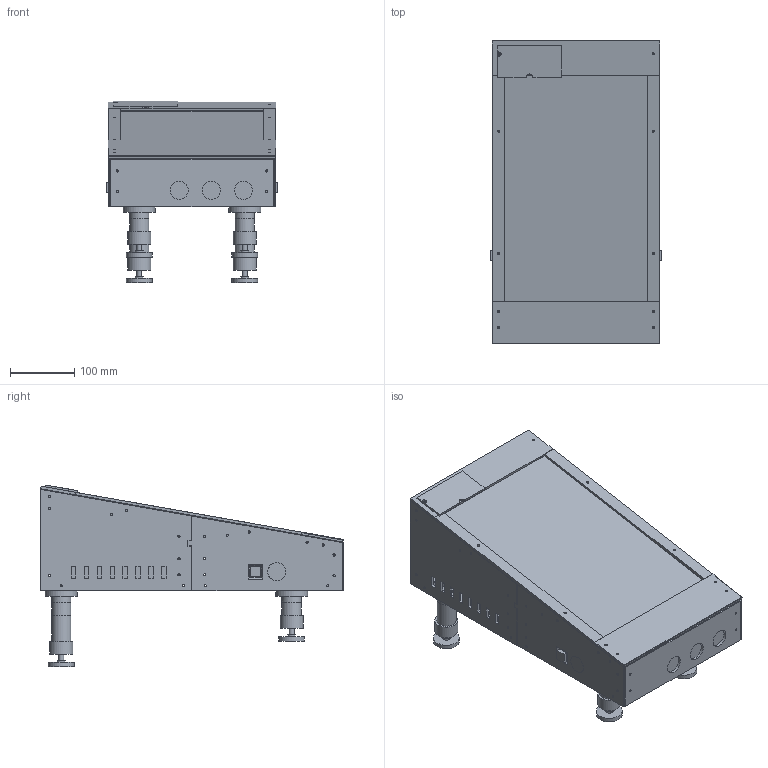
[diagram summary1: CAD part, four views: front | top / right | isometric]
STEP (ISO 10303-21) file: header records copied from the file, then geometry measured from it (millimetres).
FILE_DESCRIPTION(('Open CASCADE Model'),'2;1');
FILE_NAME('Open CASCADE Shape Model','2026-11-09T00:20:32',('Author'),( 'Open CASCADE'),'Open CASCADE STEP processor 7.8','Open CASCADE 7.8' ,'Unknown');
FILE_SCHEMA(('AUTOMOTIVE_DESIGN { 1 0 10303 214 1 1 1 1 }'));
Length unit declared in the file: millimetre
Products named in the file (89): Mini_VPin_Prototype_V1_12; left_front_wall; left_rear_wall; right_front_wall; right_rear_wall; front_button_panel; rear_vent_panel; corner_left_front_24; corner_left_front_56; corner_left_rear_24; corner_left_rear_128; corner_right_front_24; corner_right_front_56; corner_right_rear_24; corner_right_rear_128; splice_left; splice_right; floor_block_left_28; floor_block_left_218; floor_block_left_252; floor_block_left_442; floor_block_right_28; floor_block_right_218; floor_block_right_252; floor_block_right_442; bottom_front; bottom_rear; foot_backing_left_front; foot_receiver_left_front; foot_extension_left_front_1_20mm; foot_terminal_left_front; REFERENCE_swivel_rubber_pad_left_front; foot_backing_left_rear; foot_receiver_left_rear; foot_extension_left_rear_1_20mm; foot_extension_left_rear_2_40mm; foot_terminal_left_rear; REFERENCE_swivel_rubber_pad_left_rear; foot_backing_right_front; foot_receiver_right_front ...
Assembly tree (88 placements, depth 2):
  Mini_VPin_Prototype_V1_12
    left_front_wall
    left_rear_wall
    right_front_wall
    right_rear_wall
    front_button_panel
    rear_vent_panel
    corner_left_front_24
    corner_left_front_56
    corner_left_rear_24
    corner_left_rear_128
    corner_right_front_24
    corner_right_front_56
    corner_right_rear_24
    corner_right_rear_128
    splice_left
    splice_right
    floor_block_left_28
    floor_block_left_218
    floor_block_left_252
    floor_block_left_442
    floor_block_right_28
    floor_block_right_218
    floor_block_right_252
    floor_block_right_442
    bottom_front
    bottom_rear
    foot_backing_left_front
    foot_receiver_left_front
    foot_extension_left_front_1_20mm
    foot_terminal_left_front
    REFERENCE_swivel_rubber_pad_left_front
    foot_backing_left_rear
    foot_receiver_left_rear
    foot_extension_left_rear_1_20mm
    foot_extension_left_rear_2_40mm
    foot_terminal_left_rear
    REFERENCE_swivel_rubber_pad_left_rear
    foot_backing_right_front
    foot_receiver_right_front
    foot_extension_right_front_1_20mm
    foot_terminal_right_front
    REFERENCE_swivel_rubber_pad_right_front
    foot_backing_right_rear
    foot_receiver_right_rear
    foot_extension_right_rear_1_20mm
    foot_extension_right_rear_2_40mm
    foot_terminal_right_rear
    REFERENCE_swivel_rubber_pad_right_rear
    top_block_left_25
    top_block_left_50
    top_block_left_140
    top_block_left_330
    top_block_left_450
    top_block_right_25
    top_block_right_50
    top_block_right_140
    top_block_right_330
    top_block_right_450
    monitor_saddle_left_180
Bounding box: 267 x 470.54 x 282.59 mm (x, y, z)
Volume: 7623923.4 mm3; surface area: 1507758.3 mm2
Topology: 88 solids, 88 shells, 1635 faces, 4087 edges, 2722 vertices
Faces by surface type: plane 1296, cylinder 313, extrusion 20, bspline 4, cone 2
Full cylindrical faces by diameter (mm): 3.4 x158, 4.5 x52, 6 x2, 6.4 x2, 8 x4, 8.4 x16, 8.7 x14, 12 x4, 27.8 x2, 28 x5, 30 x10, 36 x4, 40 x6, 50 x8
Entity records: 114635 total; most frequent: CARTESIAN_POINT 29486, DIRECTION 14993, VECTOR 9529, LINE 9509, ORIENTED_EDGE 8174, PCURVE 8174, DEFINITIONAL_REPRESENTATION 8174, EDGE_CURVE 4087
One B-rep face of a CAD part: STEP entity #116369.
In plain terms, the planar face has unit normal (0, -0.174, 0.985).
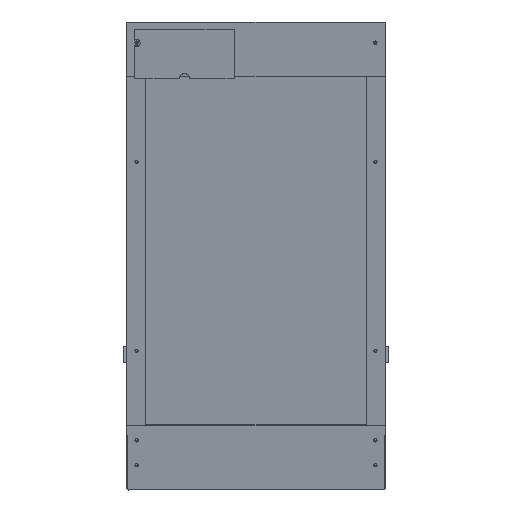
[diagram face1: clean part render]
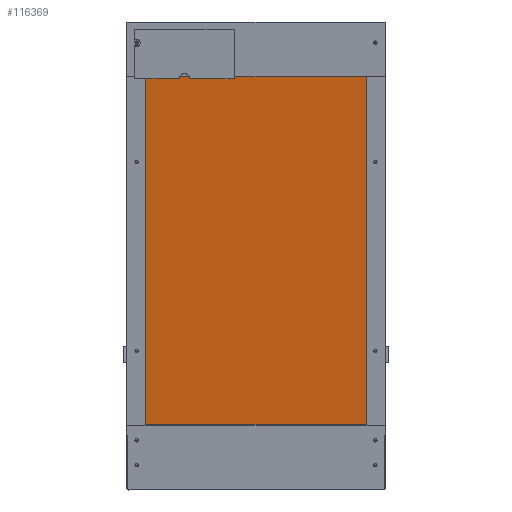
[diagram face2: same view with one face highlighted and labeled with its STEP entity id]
Its self-contained STEP definition (entity closure, numbers rounded to 3 decimals):
#116200 = PLANE('',#116201);
#116201 = AXIS2_PLACEMENT_3D('',#116202,#116203,#116204);
#116202 = CARTESIAN_POINT('',(18.1,64.,86.285));
#116203 = DIRECTION('',(-0.,1.,0.));
#116204 = DIRECTION('',(0.,0.,-1.));
#116228 = PLANE('',#116229);
#116229 = AXIS2_PLACEMENT_3D('',#116230,#116231,#116232);
#116230 = CARTESIAN_POINT('',(241.9,240.675,111.437));
#116231 = DIRECTION('',(1.,0.,0.));
#116232 = DIRECTION('',(-0.,0.,1.));
#116256 = PLANE('',#116257);
#116257 = AXIS2_PLACEMENT_3D('',#116258,#116259,#116260);
#116258 = CARTESIAN_POINT('',(18.1,417.349,136.59));
#116259 = DIRECTION('',(0.,-1.,0.));
#116260 = DIRECTION('',(0.,0.,1.));
#116282 = PLANE('',#116283);
#116283 = AXIS2_PLACEMENT_3D('',#116284,#116285,#116286);
#116284 = CARTESIAN_POINT('',(18.1,240.675,111.437));
#116285 = DIRECTION('',(1.,0.,0.));
#116286 = DIRECTION('',(-0.,0.,1.));
#116299 = VERTEX_POINT('',#116300);
#116300 = CARTESIAN_POINT('',(241.9,417.349,148.59));
#116321 = EDGE_CURVE('',#116322,#116299,#116324,.T.);
#116322 = VERTEX_POINT('',#116323);
#116323 = CARTESIAN_POINT('',(18.1,417.349,148.59));
#116324 = SURFACE_CURVE('',#116325,(#116329,#116336),.PCURVE_S1.);
#116325 = LINE('',#116326,#116327);
#116326 = CARTESIAN_POINT('',(18.1,417.349,148.59));
#116327 = VECTOR('',#116328,1.);
#116328 = DIRECTION('',(1.,0.,0.));
#116329 = PCURVE('',#116256,#116330);
#116330 = DEFINITIONAL_REPRESENTATION('',(#116331),#116335);
#116331 = LINE('',#116332,#116333);
#116332 = CARTESIAN_POINT('',(12.,0.));
#116333 = VECTOR('',#116334,1.);
#116334 = DIRECTION('',(0.,-1.));
#116335 = ( GEOMETRIC_REPRESENTATION_CONTEXT(2) 
PARAMETRIC_REPRESENTATION_CONTEXT() REPRESENTATION_CONTEXT('2D SPACE',''
  ) );
#116336 = PCURVE('',#116337,#116342);
#116337 = PLANE('',#116338);
#116338 = AXIS2_PLACEMENT_3D('',#116339,#116340,#116341);
#116339 = CARTESIAN_POINT('',(18.1,417.349,148.59));
#116340 = DIRECTION('',(0.,0.174,-0.985));
#116341 = DIRECTION('',(0.,-0.985,-0.174));
#116342 = DEFINITIONAL_REPRESENTATION('',(#116343),#116347);
#116343 = LINE('',#116344,#116345);
#116344 = CARTESIAN_POINT('',(0.,0.));
#116345 = VECTOR('',#116346,1.);
#116346 = DIRECTION('',(0.,-1.));
#116347 = ( GEOMETRIC_REPRESENTATION_CONTEXT(2) 
PARAMETRIC_REPRESENTATION_CONTEXT() REPRESENTATION_CONTEXT('2D SPACE',''
  ) );
#116369 = ADVANCED_FACE('',(#116370),#116337,.F.);
#116370 = FACE_BOUND('',#116371,.F.);
#116371 = EDGE_LOOP('',(#116372,#116373,#116396,#116419));
#116372 = ORIENTED_EDGE('',*,*,#116321,.T.);
#116373 = ORIENTED_EDGE('',*,*,#116374,.T.);
#116374 = EDGE_CURVE('',#116299,#116375,#116377,.T.);
#116375 = VERTEX_POINT('',#116376);
#116376 = CARTESIAN_POINT('',(241.9,64.,86.285));
#116377 = SURFACE_CURVE('',#116378,(#116382,#116389),.PCURVE_S1.);
#116378 = LINE('',#116379,#116380);
#116379 = CARTESIAN_POINT('',(241.9,417.349,148.59));
#116380 = VECTOR('',#116381,1.);
#116381 = DIRECTION('',(0.,-0.985,-0.174));
#116382 = PCURVE('',#116337,#116383);
#116383 = DEFINITIONAL_REPRESENTATION('',(#116384),#116388);
#116384 = LINE('',#116385,#116386);
#116385 = CARTESIAN_POINT('',(0.,-223.8));
#116386 = VECTOR('',#116387,1.);
#116387 = DIRECTION('',(1.,0.));
#116388 = ( GEOMETRIC_REPRESENTATION_CONTEXT(2) 
PARAMETRIC_REPRESENTATION_CONTEXT() REPRESENTATION_CONTEXT('2D SPACE',''
  ) );
#116389 = PCURVE('',#116228,#116390);
#116390 = DEFINITIONAL_REPRESENTATION('',(#116391),#116395);
#116391 = LINE('',#116392,#116393);
#116392 = CARTESIAN_POINT('',(37.152,-176.675));
#116393 = VECTOR('',#116394,1.);
#116394 = DIRECTION('',(-0.174,0.985));
#116395 = ( GEOMETRIC_REPRESENTATION_CONTEXT(2) 
PARAMETRIC_REPRESENTATION_CONTEXT() REPRESENTATION_CONTEXT('2D SPACE',''
  ) );
#116396 = ORIENTED_EDGE('',*,*,#116397,.F.);
#116397 = EDGE_CURVE('',#116398,#116375,#116400,.T.);
#116398 = VERTEX_POINT('',#116399);
#116399 = CARTESIAN_POINT('',(18.1,64.,86.285));
#116400 = SURFACE_CURVE('',#116401,(#116405,#116412),.PCURVE_S1.);
#116401 = LINE('',#116402,#116403);
#116402 = CARTESIAN_POINT('',(18.1,64.,86.285));
#116403 = VECTOR('',#116404,1.);
#116404 = DIRECTION('',(1.,0.,0.));
#116405 = PCURVE('',#116337,#116406);
#116406 = DEFINITIONAL_REPRESENTATION('',(#116407),#116411);
#116407 = LINE('',#116408,#116409);
#116408 = CARTESIAN_POINT('',(358.8,0.));
#116409 = VECTOR('',#116410,1.);
#116410 = DIRECTION('',(0.,-1.));
#116411 = ( GEOMETRIC_REPRESENTATION_CONTEXT(2) 
PARAMETRIC_REPRESENTATION_CONTEXT() REPRESENTATION_CONTEXT('2D SPACE',''
  ) );
#116412 = PCURVE('',#116200,#116413);
#116413 = DEFINITIONAL_REPRESENTATION('',(#116414),#116418);
#116414 = LINE('',#116415,#116416);
#116415 = CARTESIAN_POINT('',(0.,0.));
#116416 = VECTOR('',#116417,1.);
#116417 = DIRECTION('',(0.,-1.));
#116418 = ( GEOMETRIC_REPRESENTATION_CONTEXT(2) 
PARAMETRIC_REPRESENTATION_CONTEXT() REPRESENTATION_CONTEXT('2D SPACE',''
  ) );
#116419 = ORIENTED_EDGE('',*,*,#116420,.F.);
#116420 = EDGE_CURVE('',#116322,#116398,#116421,.T.);
#116421 = SURFACE_CURVE('',#116422,(#116426,#116433),.PCURVE_S1.);
#116422 = LINE('',#116423,#116424);
#116423 = CARTESIAN_POINT('',(18.1,417.349,148.59));
#116424 = VECTOR('',#116425,1.);
#116425 = DIRECTION('',(0.,-0.985,-0.174));
#116426 = PCURVE('',#116337,#116427);
#116427 = DEFINITIONAL_REPRESENTATION('',(#116428),#116432);
#116428 = LINE('',#116429,#116430);
#116429 = CARTESIAN_POINT('',(0.,0.));
#116430 = VECTOR('',#116431,1.);
#116431 = DIRECTION('',(1.,0.));
#116432 = ( GEOMETRIC_REPRESENTATION_CONTEXT(2) 
PARAMETRIC_REPRESENTATION_CONTEXT() REPRESENTATION_CONTEXT('2D SPACE',''
  ) );
#116433 = PCURVE('',#116282,#116434);
#116434 = DEFINITIONAL_REPRESENTATION('',(#116435),#116439);
#116435 = LINE('',#116436,#116437);
#116436 = CARTESIAN_POINT('',(37.152,-176.675));
#116437 = VECTOR('',#116438,1.);
#116438 = DIRECTION('',(-0.174,0.985));
#116439 = ( GEOMETRIC_REPRESENTATION_CONTEXT(2) 
PARAMETRIC_REPRESENTATION_CONTEXT() REPRESENTATION_CONTEXT('2D SPACE',''
  ) );
